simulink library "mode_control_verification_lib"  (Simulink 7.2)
settings: Solver=ode45  StartTime=0.0  StopTime=10.0  RelTol=1e-3
undefined symbols (not defined in the file or in its folder): sldvsubsys
libraries: mode_control_verification_lib x1

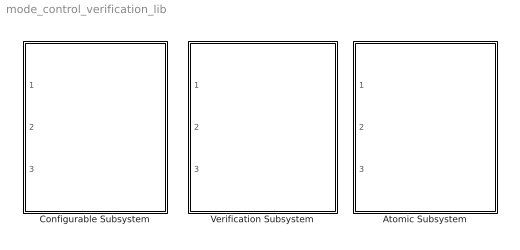
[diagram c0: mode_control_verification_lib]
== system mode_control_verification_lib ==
  Atomic Subsystem : Subsystem  TreatAsAtomicUnit=on
  Configurable Subsystem : Subsystem  BlockChoice=Verification Subsystem
  Verification Subsystem : Subsystem  Tag=VerificationSubsystem  DisableCoverage=on  LoadFcn=sldvsubsys('check')  TreatAsAtomicUnit=on  SimViewingDevice=on

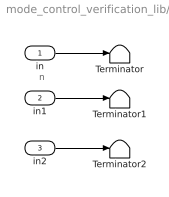
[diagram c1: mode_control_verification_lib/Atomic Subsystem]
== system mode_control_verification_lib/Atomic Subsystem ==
  note: n
  in : Inport  OutDataType=sfix(16)  OutScaling=2^0
  in1 : Inport  Port=2  OutDataType=sfix(16)  OutScaling=2^0
  in2 : Inport  Port=3  OutDataType=sfix(16)  OutScaling=2^0
  Terminator : Terminator
  Terminator1 : Terminator
  Terminator2 : Terminator
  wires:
  in/1 -> Terminator/1
  in1/1 -> Terminator1/1
  in2/1 -> Terminator2/1

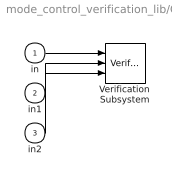
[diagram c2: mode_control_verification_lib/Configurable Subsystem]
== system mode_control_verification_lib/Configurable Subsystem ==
  in : Inport
  in1 : Inport  Port=2
  in2 : Inport  Port=3
  Verification Subsystem : mode_control_verification_lib/Verification Subsystem  Tag=VerificationSubsystem  DisableCoverage=on  SystemSampleTime=-1
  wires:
  in/1 -> Verification Subsystem/1
  in1/1 -> Verification Subsystem/2
  in2/1 -> Verification Subsystem/3

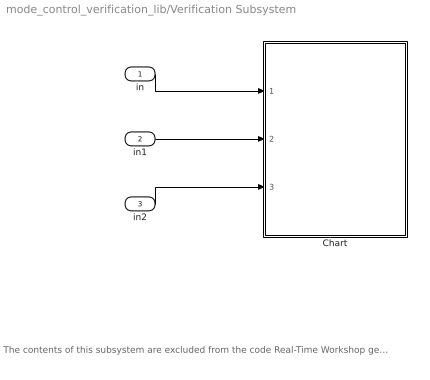
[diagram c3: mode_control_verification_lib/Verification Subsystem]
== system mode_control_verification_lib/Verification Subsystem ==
  note: The contents of this subsystem are excluded from the code Real-Time Workshop generates. To work correctly this system must continue to * Contain no output ports * Enable its 'Treat as Atomic Unit' parameter * Specify its 'Mask type' parameter as "VerificationSubsystem"
  in : Inport  OutDataType=sfix(16)  OutScaling=2^0
  in1 : Inport  Port=2  OutDataType=sfix(16)  OutScaling=2^0
  in2 : Inport  Port=3  OutDataType=sfix(16)  OutScaling=2^0
  Chart : Stateflow chart
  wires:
  in/1 -> Chart/1(exhaust_in)
  in1/1 -> Chart/2(feed_in)
  in2/1 -> Chart/3(scan_in)

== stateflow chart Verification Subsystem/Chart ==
  state status  =  Test(eahaust, feed, scan, scan_last, ScanMode_last_in) [function]
    (default) -> (junction 4)
    (junction 4) -> (junction 5) : { /* Condition #1: 超音波センサが異常 */ aVarTruthTableCondition_1 = (sensorWD == 0); }
    (junction 5) -> (junction 6) : { /* Condition #2: 後輪駆動モーター指令値が0より大 */ aVarTruthTableCondition_2 = (speed > 0); }
    (junction 6) -> (junction 7) : { /* Condition #3: 後輪駆動モータ指令値が0 */ aVarTruthTableCondition_3 = (speed == 0); }
    (junction 7) -> (junction 8) : { /* Condition #4: 後輪駆動モーター指令値が0より小 */ aVarTruthTableCondition_4 = (speed < 0); }
    (junction 8) -> (junction 9) : { /* Condition #5: 超音波センサ計測データが50[cm]より大きい */ aVarTruthTableCondition_5 = (distance > 50); }
    (junction 9) -> (junction 10) : { /* Condition #6: 超音波センサ計測データが40[cm]より大きく、かつ50[cm]以内 */ aVarTruthTableCondition_6 = (distance > 40 && distance <= 50); }
    (junction 10) -> (junction 11) : { /* Condition #7: 超音波センサ計測データが30[cm]より大きく、かつ40[cm]以内 */ aVarTruthTableCondition_7 = (distance > 30 && distance <= 40); }
    (junction 11) -> (junction 12) : { /* Condition #8: 超音波センサ計測データが30[cm]以内 */ aVarTruthTableCondition_8 = (distance <= 30); }
    (junction 12) -> (junction 13) : { /* Condition #9: 後輪駆動モータ指令値を後輪駆動モータPWM出力値に設定 */ aVarTruthTableCondition_9 = (pwm == speed); }
    (junction 13) -> (junction 14) : { /* Condition #10: 後輪駆動モータPWM出力値に0設定 */ aVarTruthTableCondition_10 = (pwm == 0); }
    (junction 14) -> (junction 15) : { /* Condition #11: 警報音出力レベルは0 */ aVarTruthTableCondition_11 = (warningLevel == 0); }
    (junction 15) -> (junction 16) : { /* Condition #12: 警報音出力レベルは1 */ aVarTruthTableCondition_12 = (warningLevel == 1); }
    (junction 16) -> (junction 17) : { /* Condition #13: 警報音出力レベルは2 */ aVarTruthTableCondition_13 = (warningLevel == 2); }
    (junction 17) -> (junction 18) : { /* Condition #14: 警報音出力レベルは3 */ aVarTruthTableCondition_14 = (warningLevel == 3); }
    (junction 18) -> (junction 19) : [aVarTruthTableCondition_1 && aVarTruthTableCondition_9 && aVarTruthTableCondition_14]   /* D1 */
    (junction 19) -> (junction 20) : { /* Action 1: 正常状態1 */ status = 1; }
    (junction 18) -> (junction 21)
    (junction 21) -> (junction 22) : [!aVarTruthTableCondition_1 && aVarTruthTableCondition_3 && aVarTruthTableCondition_9 && aVarTruthTableCondition_11]   /* D2 */
    (junction 22) -> (junction 23) : { /* Action 2: 正常状態2 */ status = 2; }
    (junction 21) -> (junction 24)
    (junction 24) -> (junction 25) : [!aVarTruthTableCondition_1 && !aVarTruthTableCondition_3 && aVarTruthTableCondition_5 && aVarTruthTableCondition_9 && aVarTruthTableCondition_11]   /* D3 */
    (junction 25) -> (junction 26) : { /* Action 3: 正常状態3 */ status = 3; }
    (junction 24) -> (junction 27)
    (junction 27) -> (junction 28) : [!aVarTruthTableCondition_1 && !aVarTruthTableCondition_3 && aVarTruthTableCondition_6 && aVarTruthTableCondition_9 && aVarTruthTableCondition_12]   /* D4 */
    (junction 28) -> (junction 29) : { /* Action 4: 正常状態4 */ status = 4; }
    (junction 27) -> (junction 30)
    (junction 30) -> (junction 31) : [!aVarTruthTableCondition_1 && !aVarTruthTableCondition_3 && aVarTruthTableCondition_7 && aVarTruthTableCondition_9 && aVarTruthTableCondition_13]   /* D5 */
    (junction 31) -> (junction 32) : { /* Action 5: 正常状態5 */ status = 5; }
    (junction 30) -> (junction 33)
    (junction 33) -> (junction 34) : [!aVarTruthTableCondition_1 && aVarTruthTableCondition_2 && aVarTruthTableCondition_8 && aVarTruthTableCondition_10 && aVarTruthTableCondition_14]   /* D6 */
    (junction 34) -> (junction 35) : { /* Action 6: 正常状態6 */ status = 6; }
    (junction 33) -> (junction 36)
    (junction 36) -> (junction 37) : [!aVarTruthTableCondition_1 && aVarTruthTableCondition_4 && aVarTruthTableCondition_8 && aVarTruthTableCondition_9 && aVarTruthTableCondition_14]   /* D7 */
    (junction 37) -> (junction 38) : { /* Action 7: 正常状態7 */ status = 7; }
    (junction 36) -> (junction 39)
    (junction 39) -> (junction 40) : /* Default */
    (junction 40) -> (junction 41) : { /* Action 8: 異常状態 */ status = 0; }
  (default) -> (junction 42) : { status_out = Test(exhaust_in, feed_in, scan_in, scan_last_in, ScanMode_last_in); scan_last_in = scan_in; ScanMode_last_in = ScanMode; }
